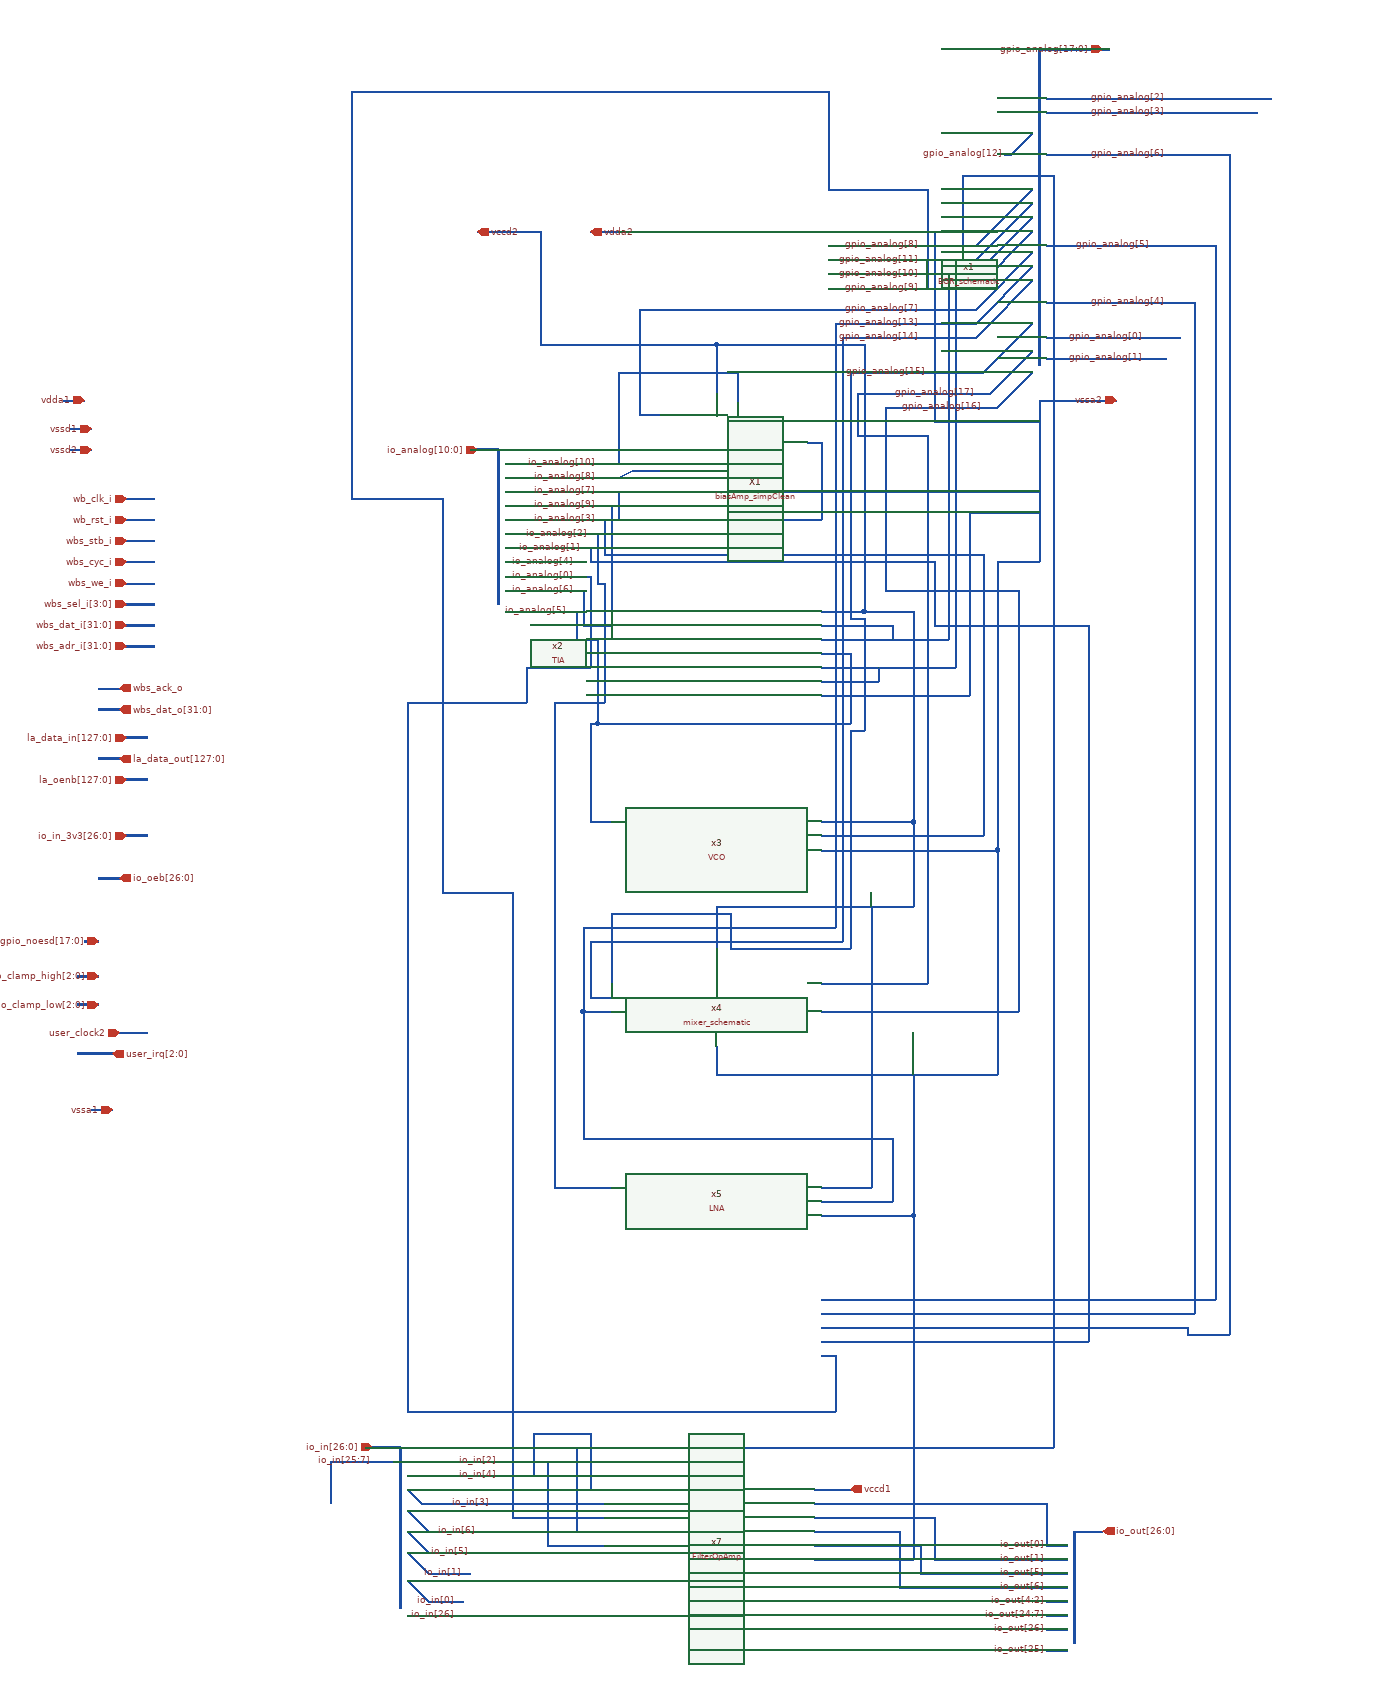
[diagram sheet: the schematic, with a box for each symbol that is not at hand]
v {xschem version=3.0.0 file_version=1.2 }
G {}
K {}
V {}
S {}
E {}
N 2220 -2160 2220 -2040 { lab=gpio_analog[17:0]
bus=true}
N 2220 -2040 2220 -2020 { lab=gpio_analog[17:0]
bus=true}
N 1920 -2040 2130 -2040 { lab=gpio_analog[8]}
N 2130 -2040 2210 -2120 { lab=gpio_analog[8]}
N 1920 -2020 2130 -2020 { lab=gpio_analog[11]}
N 2130 -2020 2210 -2100 { lab=gpio_analog[11]}
N 1920 -2000 2130 -2000 { lab=gpio_analog[10]}
N 2130 -2000 2210 -2080 { lab=gpio_analog[10]}
N 1920 -1980 2130 -1980 { lab=gpio_analog[9]}
N 2130 -1980 2210 -2060 { lab=gpio_analog[9]}
N 2220 -1820 2330 -1820 { lab=vssa2}
N 2220 -1820 2220 -1590 { lab=vssa2}
N 1920 -2060 2070 -2060 { lab=vssa2}
N 2070 -2060 2070 -1790 { lab=vssa2}
N 2070 -1790 2210 -1790 { lab=vssa2}
N 2210 -1790 2220 -1790 { lab=vssa2}
N 1760 -1900 1760 -1830 { lab=vccd2}
N 1510 -1900 1760 -1900 { lab=vccd2}
N 1510 -2060 1510 -1900 { lab=vccd2}
N 1760 -1690 2220 -1690 { lab=vssa2}
N 1410 -1750 1450 -1750 { lab=io_analog[10:0]
bus=true}
N 1460 -1730 1550 -1730 { lab=io_analog[10]}
N 1550 -1730 1620 -1730 { lab=io_analog[10]}
N 1620 -1860 1620 -1730 { lab=io_analog[10]}
N 1620 -1860 1790 -1860 { lab=io_analog[10]}
N 1460 -1710 1620 -1710 { lab=io_analog[8]}
N 1620 -1710 1640 -1720 { lab=io_analog[8]}
N 1640 -1720 1680 -1720 { lab=io_analog[8]}
N 1650 -1800 1680 -1800 { lab=gpio_analog[7]}
N 1650 -1920 1650 -1800 { lab=gpio_analog[7]}
N 1650 -1950 1650 -1920 { lab=gpio_analog[7]}
N 1650 -1950 2130 -1950 { lab=gpio_analog[7]}
N 2130 -1950 2210 -2030 { lab=gpio_analog[7]}
N 1460 -1690 1620 -1690 { lab=io_analog[7]}
N 1620 -1690 1620 -1650 { lab=io_analog[7]}
N 1620 -1650 1910 -1650 { lab=io_analog[7]}
N 1910 -1760 1910 -1650 { lab=io_analog[7]}
N 1890 -1760 1910 -1760 { lab=io_analog[7]}
N 1910 -1520 1970 -1520 { lab=vccd2}
N 1970 -1900 1970 -1520 { lab=vccd2}
N 1760 -1900 1970 -1900 { lab=vccd2}
N 1910 -1400 2120 -1400 { lab=vssa2}
N 2120 -1660 2120 -1400 { lab=vssa2}
N 2120 -1660 2220 -1660 { lab=vssa2}
N 1910 -1480 2090 -1480 { lab=gpio_analog[10]}
N 2090 -2000 2090 -1480 { lab=gpio_analog[10]}
N 1910 -1500 2010 -1500 { lab=gpio_analog[10]}
N 2010 -1500 2010 -1480 { lab=gpio_analog[10]}
N 1910 -1440 2100 -1440 { lab=gpio_analog[11]}
N 2100 -2020 2100 -1440 { lab=gpio_analog[11]}
N 1460 -1670 1610 -1670 { lab=io_analog[9]}
N 1610 -1670 1610 -1520 { lab=io_analog[9]}
N 1910 -1420 1990 -1420 { lab=gpio_analog[11]}
N 1990 -1440 1990 -1420 { lab=gpio_analog[11]}
N 1590 -1480 1590 -1360 { lab=io_analog[5]}
N 1590 -1360 1950 -1360 { lab=io_analog[5]}
N 1950 -1460 1950 -1360 { lab=io_analog[5]}
N 1910 -1460 1950 -1460 { lab=io_analog[5]}
N 1580 -1220 1610 -1220 { lab=io_analog[5]}
N 1580 -1360 1580 -1220 { lab=io_analog[5]}
N 1580 -1360 1590 -1360 { lab=io_analog[5]}
N 1910 -1180 2160 -1180 { lab=vssa2}
N 2160 -1590 2160 -1180 { lab=vssa2}
N 2160 -1590 2220 -1590 { lab=vssa2}
N 1910 -1220 1960 -1220 { lab=vccd2}
N 2040 -1520 2040 -1300 { lab=vccd2}
N 1970 -1520 2040 -1520 { lab=vccd2}
N 1960 -1220 2040 -1220 { lab=vccd2}
N 2040 -1300 2040 -1220 { lab=vccd2}
N 1460 -1650 1600 -1650 { lab=io_analog[3]}
N 1600 -1650 1600 -1600 { lab=io_analog[3]}
N 1600 -1600 2140 -1600 { lab=io_analog[3]}
N 2140 -1600 2140 -1200 { lab=io_analog[3]}
N 1910 -1200 2140 -1200 { lab=io_analog[3]}
N 1760 -1100 1760 -1040 { lab=vccd2}
N 1760 -1100 2040 -1100 { lab=vccd2}
N 2040 -1220 2040 -1100 { lab=vccd2}
N 1760 -900 1760 -860 { lab=vssa2}
N 1760 -860 2160 -860 { lab=vssa2}
N 2160 -1180 2160 -860 { lab=vssa2}
N 1570 -1070 1570 -950 { lab=gpio_analog[13]}
N 1570 -950 1610 -950 { lab=gpio_analog[13]}
N 2130 -1930 2210 -2010 { lab=gpio_analog[13]}
N 1930 -1930 2130 -1930 { lab=gpio_analog[13]}
N 1930 -1930 1930 -1070 { lab=gpio_analog[13]}
N 1570 -1070 1930 -1070 { lab=gpio_analog[13]}
N 2220 -2020 2220 -1940 { lab=gpio_analog[17:0]
bus=true}
N 2140 -1920 2210 -1990 { lab=gpio_analog[14]}
N 2130 -1910 2140 -1920 { lab=gpio_analog[14]}
N 1940 -1910 2130 -1910 { lab=gpio_analog[14]}
N 1940 -1910 1940 -1050 { lab=gpio_analog[14]}
N 1580 -1050 1940 -1050 { lab=gpio_analog[14]}
N 1580 -1050 1580 -970 { lab=gpio_analog[14]}
N 1580 -970 1610 -970 { lab=gpio_analog[14]}
N 2140 -1860 2210 -1930 { lab=gpio_analog[15]}
N 1950 -1860 2140 -1860 { lab=gpio_analog[15]}
N 1780 -1040 1950 -1040 { lab=gpio_analog[15]}
N 1780 -1090 1780 -1040 { lab=gpio_analog[15]}
N 1610 -1090 1780 -1090 { lab=gpio_analog[15]}
N 1610 -1090 1610 -990 { lab=gpio_analog[15]}
N 2220 -1940 2220 -1900 { lab=gpio_analog[17:0]
bus=true}
N 2150 -1830 2210 -1890 { lab=gpio_analog[17]}
N 1960 -1830 2150 -1830 { lab=gpio_analog[17]}
N 1910 -990 1960 -990 { lab=gpio_analog[17]}
N 1960 -1830 1960 -1770 { lab=gpio_analog[17]}
N 1960 -1770 2060 -1770 { lab=gpio_analog[17]}
N 2060 -1770 2060 -990 { lab=gpio_analog[17]}
N 1960 -990 2060 -990 { lab=gpio_analog[17]}
N 2220 -1900 2220 -1870 { lab=gpio_analog[17:0]
bus=true}
N 2160 -1810 2210 -1860 { lab=gpio_analog[16]}
N 2000 -1810 2160 -1810 { lab=gpio_analog[16]}
N 2000 -1810 2000 -1550 { lab=gpio_analog[16]}
N 2000 -1550 2190 -1550 { lab=gpio_analog[16]}
N 2190 -1550 2190 -950 { lab=gpio_analog[16]}
N 1910 -950 2190 -950 { lab=gpio_analog[16]}
N 1910 -700 1980 -700 { lab=vccd2}
N 1980 -1100 1980 -700 { lab=vccd2}
N 1910 -660 2040 -660 { lab=vssa2}
N 2040 -860 2040 -660 { lab=vssa2}
N 1530 -700 1610 -700 { lab=io_analog[2]}
N 1530 -1090 1530 -700 { lab=io_analog[2]}
N 1570 -950 1570 -770 { lab=gpio_analog[13]}
N 1570 -770 2010 -770 { lab=gpio_analog[13]}
N 2010 -770 2010 -680 { lab=gpio_analog[13]}
N 1910 -680 2010 -680 { lab=gpio_analog[13]}
N 1900 -270 1950 -270 { lab=vccd1}
N 2040 -660 2040 -170 { lab=vssa2}
N 1560 -210 1600 -210 { lab=gpio_analog[8]}
N 1560 -280 1560 -210 { lab=gpio_analog[8]}
N 1560 -330 1560 -280 { lab=gpio_analog[8]}
N 1560 -330 2100 -330 { lab=gpio_analog[8]}
N 2100 -330 2240 -330 { lab=gpio_analog[8]}
N 2240 -2140 2240 -330 { lab=gpio_analog[8]}
N 2110 -2140 2240 -2140 { lab=gpio_analog[8]}
N 2110 -2140 2110 -2040 { lab=gpio_analog[8]}
N 1460 -1630 1590 -1630 { lab=io_analog[2]}
N 1590 -1630 1590 -1560 { lab=io_analog[2]}
N 1590 -1560 1600 -1560 { lab=io_analog[2]}
N 1600 -1560 1600 -1390 { lab=io_analog[2]}
N 1540 -1390 1600 -1390 { lab=io_analog[2]}
N 1530 -1390 1540 -1390 { lab=io_analog[2]}
N 1530 -1390 1530 -1090 { lab=io_analog[2]}
N 1520 -190 1600 -190 { lab=io_in[2]}
N 1260 -330 1310 -330 { lab=io_in[26:0]
bus=true}
N 1310 -330 1310 -280 { lab=io_in[26:0]
bus=true}
N 1320 -310 1520 -310 { lab=io_in[2]}
N 1520 -310 1520 -190 { lab=io_in[2]}
N 1580 -270 1600 -270 { lab=io_in[4]}
N 1580 -350 1580 -270 { lab=io_in[4]}
N 1320 -290 1500 -290 { lab=io_in[4]}
N 1500 -350 1500 -290 { lab=io_in[4]}
N 1500 -350 1580 -350 { lab=io_in[4]}
N 1490 -230 1600 -230 { lab=gpio_analog[9]}
N 2220 -2320 2220 -2160 { lab=gpio_analog[17:0]
bus=true}
N 2220 -2320 2320 -2320 { lab=gpio_analog[17:0]
bus=true}
N 1470 -230 1490 -230 { lab=gpio_analog[9]}
N 1470 -1120 1470 -230 { lab=gpio_analog[9]}
N 1370 -1120 1470 -1120 { lab=gpio_analog[9]}
N 1370 -1680 1370 -1120 { lab=gpio_analog[9]}
N 1240 -1680 1370 -1680 { lab=gpio_analog[9]}
N 1240 -2250 1240 -1680 { lab=gpio_analog[9]}
N 1240 -2260 1240 -2250 { lab=gpio_analog[9]}
N 1240 -2260 1920 -2260 { lab=gpio_analog[9]}
N 1380 -250 1600 -250 { lab=io_in[3]}
N 1320 -270 1340 -250 { lab=io_in[3]}
N 1340 -250 1380 -250 { lab=io_in[3]}
N 1900 -210 1960 -210 { lab=io_out[6]}
N 1310 -280 1310 -240 { lab=io_in[26:0]
bus=true}
N 1320 -240 1350 -210 { lab=io_in[6]}
N 1350 -210 1430 -210 { lab=io_in[6]}
N 1900 -190 1990 -190 { lab=io_out[5]}
N 1310 -240 1310 -220 { lab=io_in[26:0]
bus=true}
N 1320 -210 1350 -180 { lab=io_in[5]}
N 1350 -180 1410 -180 { lab=io_in[5]}
N 1410 -180 1420 -180 { lab=io_in[5]}
N 1900 -230 2070 -230 { lab=io_out[1]}
N 1310 -220 1310 -150 { lab=io_in[26:0]
bus=true}
N 1320 -180 1350 -150 { lab=io_in[1]}
N 1350 -150 1410 -150 { lab=io_in[1]}
N 1320 -140 1350 -110 { lab=io_in[0]}
N 1350 -110 1400 -110 { lab=io_in[0]}
N 1900 -250 2020 -250 { lab=io_out[0]}
N 1460 -1610 1580 -1610 { lab=io_analog[1]}
N 1580 -1610 1580 -1590 { lab=io_analog[1]}
N 1580 -1590 2070 -1590 { lab=io_analog[1]}
N 2070 -1590 2070 -1500 { lab=io_analog[1]}
N 2070 -1500 2290 -1500 { lab=io_analog[1]}
N 1910 -480 2290 -480 { lab=io_analog[1]}
N 2290 -1500 2290 -480 { lab=io_analog[1]}
N 1320 -380 1930 -380 { lab=io_analog[0]}
N 1320 -1390 1320 -380 { lab=io_analog[0]}
N 1320 -1390 1490 -1390 { lab=io_analog[0]}
N 1490 -1440 1490 -1390 { lab=io_analog[0]}
N 1490 -1440 1580 -1440 { lab=io_analog[0]}
N 1580 -1570 1580 -1440 { lab=io_analog[0]}
N 1470 -1570 1580 -1570 { lab=io_analog[0]}
N 1460 -1570 1470 -1570 { lab=io_analog[0]}
N 2230 -1960 2280 -1960 { lab=gpio_analog[4]}
N 2280 -1960 2440 -1960 { lab=gpio_analog[4]}
N 2440 -1960 2440 -530 { lab=gpio_analog[4]}
N 1910 -520 2440 -520 { lab=gpio_analog[4]}
N 2440 -530 2440 -520 { lab=gpio_analog[4]}
N 2230 -2040 2470 -2040 { lab=gpio_analog[5]}
N 2470 -2040 2470 -540 { lab=gpio_analog[5]}
N 1910 -540 2470 -540 { lab=gpio_analog[5]}
N 2230 -2170 2490 -2170 { lab=gpio_analog[6]}
N 2490 -2170 2490 -490 { lab=gpio_analog[6]}
N 1910 -500 2430 -500 { lab=gpio_analog[6]}
N 2430 -500 2430 -490 { lab=gpio_analog[6]}
N 2430 -490 2490 -490 { lab=gpio_analog[6]}
N 2230 -2230 2530 -2230 { lab=gpio_analog[3]}
N 1920 -2260 1920 -2120 { lab=gpio_analog[9]}
N 1920 -2120 2060 -2120 { lab=gpio_analog[9]}
N 2060 -2120 2060 -1980 { lab=gpio_analog[9]}
N 1420 -2060 1510 -2060 { lab=vccd2}
N 1580 -2060 1620 -2060 { lab=vdda2}
N 2180 -2170 2210 -2200 { lab=gpio_analog[12]}
N 2170 -2170 2180 -2170 { lab=gpio_analog[12]}
N 1450 -1750 1450 -1580 { lab=io_analog[10:0]
bus=true}
N 1450 -1580 1450 -1560 { lab=io_analog[10:0]
bus=true}
N 1460 -1550 1570 -1550 { lab=io_analog[6]}
N 1570 -1550 1570 -1500 { lab=io_analog[6]}
N 1570 -1500 1610 -1500 { lab=io_analog[6]}
N 1450 -1560 1450 -1530 { lab=io_analog[10:0]
bus=true}
N 1460 -1520 1560 -1520 { lab=io_analog[5]}
N 1560 -1520 1560 -1480 { lab=io_analog[5]}
N 1560 -1480 1590 -1480 { lab=io_analog[5]}
N 1460 -1590 1570 -1590 { lab=io_analog[4]}
N 2230 -1880 2400 -1880 { lab=gpio_analog[1]}
N 2230 -1910 2420 -1910 { lab=gpio_analog[0]}
N 1270 -310 1300 -310 { lab=io_in[25:7]}
N 1210 -310 1270 -310 { lab=io_in[25:7]}
N 1210 -310 1210 -250 { lab=io_in[25:7]}
N 840 -1780 870 -1780 { lab=vssd1}
N 840 -1750 870 -1750 { lab=vssd2}
N 920 -1680 960 -1680 { lab=wb_clk_i}
N 920 -1650 960 -1650 { lab=wb_rst_i}
N 920 -1620 960 -1620 { lab=wbs_stb_i}
N 920 -1590 960 -1590 { lab=wbs_cyc_i}
N 920 -1560 960 -1560 { lab=wbs_we_i}
N 920 -1530 960 -1530 { lab=wbs_sel_i[3:0]
bus=true}
N 920 -1500 960 -1500 { lab=wbs_dat_i[31:0]
bus=true}
N 920 -1470 960 -1470 { lab=wbs_adr_i[31:0]
bus=true}
N 880 -1410 910 -1410 { lab=wbs_ack_o}
N 880 -1380 910 -1380 { lab=wbs_dat_o[31:0]
bus=true}
N 920 -1340 950 -1340 { lab=la_data_in[127:0]
bus=true
}
N 880 -1310 910 -1310 { lab=la_data_out[127:0]
bus=true}
N 920 -1280 950 -1280 { lab=la_oenb[127:0]
bus=true
}
N 920 -1200 950 -1200 { lab=io_in_3v3[26:0]
bus=true}
N 880 -1140 910 -1140 { lab=io_oeb[26:0]
bus=true}
N 860 -1050 880 -1050 { lab=gpio_noesd[17:0]
bus=true}
N 850 -960 880 -960 { lab=io_clamp_low[2:0]
bus=true}
N 910 -920 950 -920 { lab=user_clock2}
N 850 -890 900 -890 { lab=user_irq[2:0]
bus=true}
N 1950 -1350 1950 -1040 { lab=gpio_analog[15]}
N 1950 -1350 1970 -1350 { lab=gpio_analog[15]}
N 1970 -1510 1970 -1350 { lab=gpio_analog[15]}
N 1950 -1510 1970 -1510 { lab=gpio_analog[15]}
N 1950 -1860 1950 -1510 { lab=gpio_analog[15]}
N 2270 -210 2310 -210 { lab=io_out[26:0]}
N 2270 -210 2270 -100 { lab=io_out[26:0]
bus=true}
N 2230 -190 2260 -190 { lab=io_out[0]}
N 2230 -170 2260 -170 { lab=io_out[1]}
N 2230 -150 2260 -150 { lab=io_out[5]}
N 2230 -130 2260 -130 { lab=io_out[6]}
N 2230 -110 2260 -110 { lab=io_out[4:2]}
N 2020 -250 2230 -250 { lab=io_out[0]}
N 2230 -250 2230 -190 { lab=io_out[0]}
N 2070 -230 2070 -180 { lab=io_out[1]}
N 2070 -180 2070 -170 { lab=io_out[1]}
N 2070 -170 2230 -170 { lab=io_out[1]}
N 1960 -210 2020 -210 { lab=io_out[6]}
N 2020 -210 2020 -130 { lab=io_out[6]}
N 2020 -130 2230 -130 { lab=io_out[6]}
N 1990 -190 2050 -190 { lab=io_out[5]}
N 2050 -190 2050 -150 { lab=io_out[5]}
N 2050 -150 2230 -150 { lab=io_out[5]}
N 2230 -90 2260 -90 { lab=io_out[24:7]}
N 1790 -1860 1790 -1817.5 { lab=io_analog[10]}
N 1310 -150 1310 -100 { lab=io_in[26:0]
bus = true}
N 1320 -90 1400 -90 { lab=io_in[26]}
N 2230 -70 2260 -70 { lab=io_out[26]}
N 2270 -100 2270 -80 { lab=io_out[26:0]
bus=true}
N 2230 -40 2260 -40 { lab=io_out[25]}
N 2270 -80 2270 -50 { lab=io_out[26:0]
bus=true}
N 1990 -170 2040 -170 { lab=vssa2}
N 1910 -460 1930 -460 { lab=io_analog[0]}
N 2530 -2250 2550 -2250 { lab=gpio_analog[2]}
N 2230 -2250 2530 -2250 { lab=gpio_analog[2]}
N 1930 -460 1930 -380 { lab=io_analog[0]}
N 870 -810 900 -810 { lab=vssa1}
N 1900 -170 1990 -170 { lab=vssa2}
N 830 -1820 860 -1820 { lab=vdda1}
N 850 -1000 880 -1000 { lab=io_clamp_high[2:0]
bus=true
}
C {iopin.sym} 900 -810 0 0 {name=p3 lab=vssa1}
C {iopin.sym} 1950 -270 2 1 {name=p5 lab=vccd1}
C {ipin.sym} 1270 -330 0 0 {name=p21 lab=io_in[26:0]}
C {iopin.sym} 2310 -2320 0 0 {name=p26 lab=gpio_analog[17:0]}
C {iopin.sym} 1420 -1750 2 0 {name=p29 lab=io_analog[10:0]}
C {/research/mlab/chipathon/Final_schematic/BGR_schematic.sym} 1770 -2020 0 0 {name=x1}
C {bus_connect_nolab.sym} 2220 -2130 2 0 {name=r1}
C {bus_connect_nolab.sym} 2220 -2110 2 0 {name=r2}
C {bus_connect_nolab.sym} 2220 -2090 2 0 {name=r3}
C {bus_connect_nolab.sym} 2220 -2070 2 0 {name=r4}
C {bus_connect_nolab.sym} 2220 -2040 2 0 {name=r5}
C {bus_connect_nolab.sym} 2220 -2020 2 0 {name=r6}
C {lab_wire.sym} 2050 -2040 0 0 {name=l33 sig_type=std_logic lab=gpio_analog[8]}
C {lab_wire.sym} 2050 -2020 0 0 {name=l34 sig_type=std_logic lab=gpio_analog[11]}
C {lab_wire.sym} 2050 -2000 0 0 {name=l35 sig_type=std_logic lab=gpio_analog[10]}
C {lab_wire.sym} 2050 -1980 0 0 {name=l36 sig_type=std_logic lab=gpio_analog[9]}
C {/research/mlab/chipathon/Final_schematic/biasAmp_simpClean.sym} 1760 -1760 0 0 {name=X1}
C {bus_connect_nolab.sym} 1450 -1740 1 0 {name=r13
}
C {lab_wire.sym} 1590 -1730 0 0 {name=l37 sig_type=std_logic lab=io_analog[10]}
C {bus_connect_nolab.sym} 1450 -1720 1 0 {name=r14
}
C {lab_wire.sym} 1590 -1710 0 0 {name=l38 sig_type=std_logic lab=io_analog[8]}
C {lab_wire.sym} 2050 -1950 0 0 {name=l39 sig_type=std_logic lab=gpio_analog[7]}
C {bus_connect_nolab.sym} 1450 -1700 1 0 {name=r15
}
C {lab_wire.sym} 1590 -1690 0 0 {name=l40 sig_type=std_logic lab=io_analog[7]}
C {bus_connect_nolab.sym} 1450 -1680 1 0 {name=r16
}
C {lab_wire.sym} 1560 -1550 0 0 {name=l42 sig_type=std_logic lab=io_analog[6]}
C {bus_connect_nolab.sym} 1450 -1530 1 0 {name=r17
}
C {/research/mlab/chipathon/Final_schematic/VCO.sym} 1760 -1200 0 0 {name=x3}
C {bus_connect_nolab.sym} 1450 -1660 1 0 {name=r18
}
C {lab_wire.sym} 1590 -1650 0 0 {name=l44 sig_type=std_logic lab=io_analog[3]}
C {/research/mlab/chipathon/Final_schematic/mixer_schematic.sym} 1760 -970 0 0 {name=x4}
C {lab_wire.sym} 2050 -1930 0 0 {name=l45 sig_type=std_logic lab=gpio_analog[13]}
C {bus_connect_nolab.sym} 2220 -2000 2 0 {name=r8}
C {lab_wire.sym} 2050 -1910 0 0 {name=l46 sig_type=std_logic lab=gpio_analog[14]}
C {bus_connect_nolab.sym} 2220 -1940 2 0 {name=r9}
C {lab_wire.sym} 2060 -1860 0 0 {name=l47 sig_type=std_logic lab=gpio_analog[15]}
C {bus_connect_nolab.sym} 2220 -1900 2 0 {name=r10}
C {lab_wire.sym} 2130 -1830 0 0 {name=l48 sig_type=std_logic lab=gpio_analog[17]}
C {bus_connect_nolab.sym} 2220 -1870 2 0 {name=r11}
C {lab_wire.sym} 2140 -1810 0 0 {name=l49 sig_type=std_logic lab=gpio_analog[16]}
C {/research/mlab/chipathon/Final_schematic/LNA.sym} 1760 -680 0 0 {name=x5}
C {/research/mlab/chipathon/Final_schematic/FilterOpAmp.sym} 1750 -220 0 0 {name=x7}
C {bus_connect_nolab.sym} 1450 -1640 1 0 {name=r27
}
C {lab_wire.sym} 1580 -1630 0 0 {name=l50 sig_type=std_logic lab=io_analog[2]}
C {bus_connect_nolab.sym} 1310 -320 1 0 {name=r19}
C {lab_wire.sym} 1450 -310 0 0 {name=l51 sig_type=std_logic lab=io_in[2]}
C {bus_connect_nolab.sym} 1310 -300 1 0 {name=r20}
C {lab_wire.sym} 1450 -290 0 0 {name=l52 sig_type=std_logic lab=io_in[4]}
C {bus_connect_nolab.sym} 1310 -280 1 0 {name=r22}
C {lab_wire.sym} 1440 -250 0 0 {name=l54 sig_type=std_logic lab=io_in[3]}
C {bus_connect_nolab.sym} 1310 -250 1 0 {name=r23}
C {lab_wire.sym} 1420 -210 0 0 {name=l55 sig_type=std_logic lab=io_in[6]}
C {bus_connect_nolab.sym} 1310 -220 1 0 {name=r24}
C {lab_wire.sym} 1410 -180 0 0 {name=l56 sig_type=std_logic lab=io_in[5]}
C {bus_connect_nolab.sym} 1310 -190 1 0 {name=r25}
C {lab_wire.sym} 1400 -150 0 0 {name=l57 sig_type=std_logic lab=io_in[1]}
C {bus_connect_nolab.sym} 1310 -150 1 0 {name=r26}
C {lab_wire.sym} 1390 -110 0 0 {name=l58 sig_type=std_logic lab=io_in[0]}
C {bus_connect_nolab.sym} 1450 -1620 1 0 {name=r28
}
C {lab_wire.sym} 1570 -1610 0 0 {name=l59 sig_type=std_logic lab=io_analog[1]}
C {bus_connect_nolab.sym} 1450 -1580 1 0 {name=r34
}
C {lab_wire.sym} 1560 -1570 0 0 {name=l60 sig_type=std_logic lab=io_analog[0]}
C {bus_connect_nolab.sym} 2220 -1970 1 0 {name=r29}
C {lab_wire.sym} 2400 -1960 0 0 {name=l61 sig_type=std_logic lab=gpio_analog[4]}
C {bus_connect_nolab.sym} 2220 -2050 1 0 {name=r30}
C {lab_wire.sym} 2380 -2040 0 0 {name=l62 sig_type=std_logic lab=gpio_analog[5]}
C {bus_connect_nolab.sym} 2220 -2180 1 0 {name=r31}
C {lab_wire.sym} 2400 -2170 0 0 {name=l63 sig_type=std_logic lab=gpio_analog[6]}
C {bus_connect_nolab.sym} 2220 -2260 1 0 {name=r32}
C {bus_connect_nolab.sym} 2220 -2240 1 0 {name=r33}
C {lab_wire.sym} 2370 -1910 0 0 {name=l64 sig_type=std_logic lab=gpio_analog[0]}
C {lab_wire.sym} 2370 -1880 0 0 {name=l65 sig_type=std_logic lab=gpio_analog[1]}
C {bus_connect_nolab.sym} 2220 -2210 2 0 {name=r21}
C {bus_connect_nolab.sym} 1450 -1560 1 0 {name=r35
}
C {lab_wire.sym} 1590 -1670 0 0 {name=l41 sig_type=std_logic lab=io_analog[9]}
C {lab_wire.sym} 1550 -1520 0 0 {name=l43 sig_type=std_logic lab=io_analog[5]}
C {bus_connect_nolab.sym} 1450 -1600 1 0 {name=r36
}
C {lab_wire.sym} 1560 -1590 0 0 {name=l66 sig_type=std_logic lab=io_analog[4]}
C {bus_connect_nolab.sym} 2220 -1920 1 0 {name=r7}
C {bus_connect_nolab.sym} 2220 -1890 1 0 {name=r12}
C {lab_wire.sym} 2400 -2250 0 0 {name=l67 sig_type=std_logic lab=gpio_analog[2]}
C {lab_wire.sym} 2400 -2230 0 0 {name=l68 sig_type=std_logic lab=gpio_analog[3]}
C {bus_connect_nolab.sym} 1310 -320 2 0 {name=r37}
C {lab_wire.sym} 1270 -310 3 0 {name=l1 sig_type=std_logic lab=io_in[25:7]}
C {noconn.sym} 1210 -250 0 0 {name=l2}
C {iopin.sym} 2330 -1820 0 0 {name=p4 lab=vssa2}
C {iopin.sym} 1420 -2060 0 1 {name=p6 lab=vccd2}
C {iopin.sym} 870 -1780 0 0 {name=p7 lab=vssd1}
C {iopin.sym} 870 -1750 0 0 {name=p8 lab=vssd2}
C {ipin.sym} 920 -1680 0 0 {name=p9 lab=wb_clk_i}
C {ipin.sym} 920 -1650 0 0 {name=p10 lab=wb_rst_i}
C {ipin.sym} 920 -1620 0 0 {name=p11 lab=wbs_stb_i}
C {ipin.sym} 920 -1590 0 0 {name=p12 lab=wbs_cyc_i}
C {ipin.sym} 920 -1560 0 0 {name=p13 lab=wbs_we_i}
C {ipin.sym} 920 -1530 0 0 {name=p14 lab=wbs_sel_i[3:0]}
C {ipin.sym} 920 -1500 0 0 {name=p15 lab=wbs_dat_i[31:0]}
C {ipin.sym} 920 -1470 0 0 {name=p16 lab=wbs_adr_i[31:0]}
C {opin.sym} 910 -1410 0 0 {name=p17 lab=wbs_ack_o}
C {opin.sym} 910 -1380 0 0 {name=p18 lab=wbs_dat_o[31:0]}
C {ipin.sym} 920 -1340 0 0 {name=p19 lab=la_data_in[127:0]}
C {opin.sym} 910 -1310 0 0 {name=p20 lab=la_data_out[127:0]}
C {ipin.sym} 920 -1200 0 0 {name=p22 lab=io_in_3v3[26:0]}
C {ipin.sym} 910 -920 0 0 {name=p23 lab=user_clock2}
C {opin.sym} 910 -1140 0 0 {name=p25 lab=io_oeb[26:0]}
C {iopin.sym} 880 -1050 0 0 {name=p27 lab=gpio_noesd[17:0]}
C {iopin.sym} 880 -960 0 0 {name=p31 lab=io_clamp_low[2:0]}
C {opin.sym} 900 -890 0 0 {name=p32 lab=user_irq[2:0]}
C {ipin.sym} 920 -1280 0 0 {name=p28 lab=la_oenb[127:0]}
C {noconn.sym} 840 -1780 0 0 {name=l75}
C {noconn.sym} 840 -1750 0 0 {name=l76}
C {noconn.sym} 960 -1680 0 1 {name=l3}
C {noconn.sym} 960 -1650 0 1 {name=l4}
C {noconn.sym} 960 -1620 0 1 {name=l5}
C {noconn.sym} 960 -1590 0 1 {name=l6}
C {noconn.sym} 960 -1560 0 1 {name=l7}
C {noconn.sym} 960 -1530 0 1 {name=l8}
C {noconn.sym} 960 -1500 0 1 {name=l9}
C {noconn.sym} 960 -1470 0 1 {name=l10}
C {noconn.sym} 880 -1410 0 0 {name=l11}
C {noconn.sym} 880 -1380 0 0 {name=l12}
C {noconn.sym} 950 -1340 0 1 {name=l13}
C {noconn.sym} 880 -1310 0 0 {name=l14}
C {noconn.sym} 950 -1280 0 1 {name=l77}
C {noconn.sym} 950 -1200 0 1 {name=l78}
C {noconn.sym} 880 -1140 0 0 {name=l80}
C {noconn.sym} 860 -1050 0 0 {name=l81}
C {noconn.sym} 850 -960 0 0 {name=l82}
C {noconn.sym} 850 -890 0 0 {name=l83}
C {noconn.sym} 950 -920 0 1 {name=l84}
C {opin.sym} 2310 -210 0 0 {name=p30 lab=io_out[26:0]}
C {bus_connect_nolab.sym} 2270 -200 2 0 {name=r38}
C {bus_connect_nolab.sym} 2270 -180 2 0 {name=r39}
C {bus_connect_nolab.sym} 2270 -160 2 0 {name=r40}
C {bus_connect_nolab.sym} 2270 -140 2 0 {name=r41}
C {bus_connect_nolab.sym} 2270 -120 2 0 {name=r42}
C {noconn.sym} 1430 -210 0 1 {name=l15}
C {noconn.sym} 1420 -180 0 1 {name=l16}
C {noconn.sym} 1410 -150 0 1 {name=l17}
C {noconn.sym} 1400 -110 0 1 {name=l18}
C {lab_wire.sym} 2230 -190 0 0 {name=l19 sig_type=std_logic lab=io_out[0]}
C {lab_wire.sym} 2230 -170 0 0 {name=l20 sig_type=std_logic lab=io_out[1]}
C {lab_wire.sym} 2230 -150 0 0 {name=l21 sig_type=std_logic lab=io_out[5]}
C {lab_wire.sym} 2230 -130 0 0 {name=l22 sig_type=std_logic lab=io_out[6]}
C {bus_connect_nolab.sym} 2270 -100 2 0 {name=r43}
C {lab_wire.sym} 2230 -110 0 0 {name=l23 sig_type=std_logic lab=io_out[4:2]}
C {lab_wire.sym} 2230 -90 0 0 {name=l24 sig_type=std_logic lab=io_out[24:7]}
C {noconn.sym} 2230 -110 0 0 {name=l25}
C {noconn.sym} 2230 -90 0 0 {name=l26}
C {bus_connect_nolab.sym} 1310 -100 1 0 {name=r44}
C {lab_wire.sym} 1390 -90 0 0 {name=l28 sig_type=std_logic lab=io_in[26]}
C {bus_connect_nolab.sym} 2270 -80 2 0 {name=r45}
C {lab_wire.sym} 2230 -70 0 0 {name=l31 sig_type=std_logic lab=io_out[26]}
C {noconn.sym} 2230 -70 0 0 {name=l32}
C {lab_wire.sym} 2230 -40 0 0 {name=l69 sig_type=std_logic lab=io_out[25]}
C {bus_connect_nolab.sym} 2270 -50 2 0 {name=r46}
C {iopin.sym} 1580 -2060 0 1 {name=p24 lab=vdda2}
C {lab_wire.sym} 2170 -2170 0 0 {name=l27 sig_type=std_logic lab=gpio_analog[12]}
C {noconn.sym} 1910 -540 0 0 {name=l70}
C {noconn.sym} 1910 -520 0 0 {name=l71}
C {noconn.sym} 1910 -500 0 0 {name=l72}
C {noconn.sym} 1910 -480 0 0 {name=l73}
C {noconn.sym} 1910 -460 0 0 {name=l74}
C {noconn.sym} 2530 -2230 0 1 {name=l86}
C {noconn.sym} 2550 -2250 0 1 {name=l87}
C {/research/mlab/chipathon/Final_schematic/TIA.sym} 1760 -1460 0 0 {name=x2}
C {noconn.sym} 1570 -1590 0 1 {name=l79}
C {noconn.sym} 870 -810 0 0 {name=l85}
C {noconn.sym} 2170 -2170 0 0 {name=l88}
C {noconn.sym} 2230 -40 0 0 {name=l53}
C {noconn.sym} 1400 -90 0 1 {name=l29}
C {noconn.sym} 2400 -1880 0 1 {name=l30}
C {noconn.sym} 2420 -1910 0 1 {name=l89}
C {iopin.sym} 860 -1820 0 0 {name=p1 lab=vdda1}
C {noconn.sym} 830 -1820 0 0 {name=l90}
C {iopin.sym} 880 -1000 0 0 {name=p2 lab=io_clamp_high[2:0]}
C {noconn.sym} 850 -1000 0 0 {name=l91}
